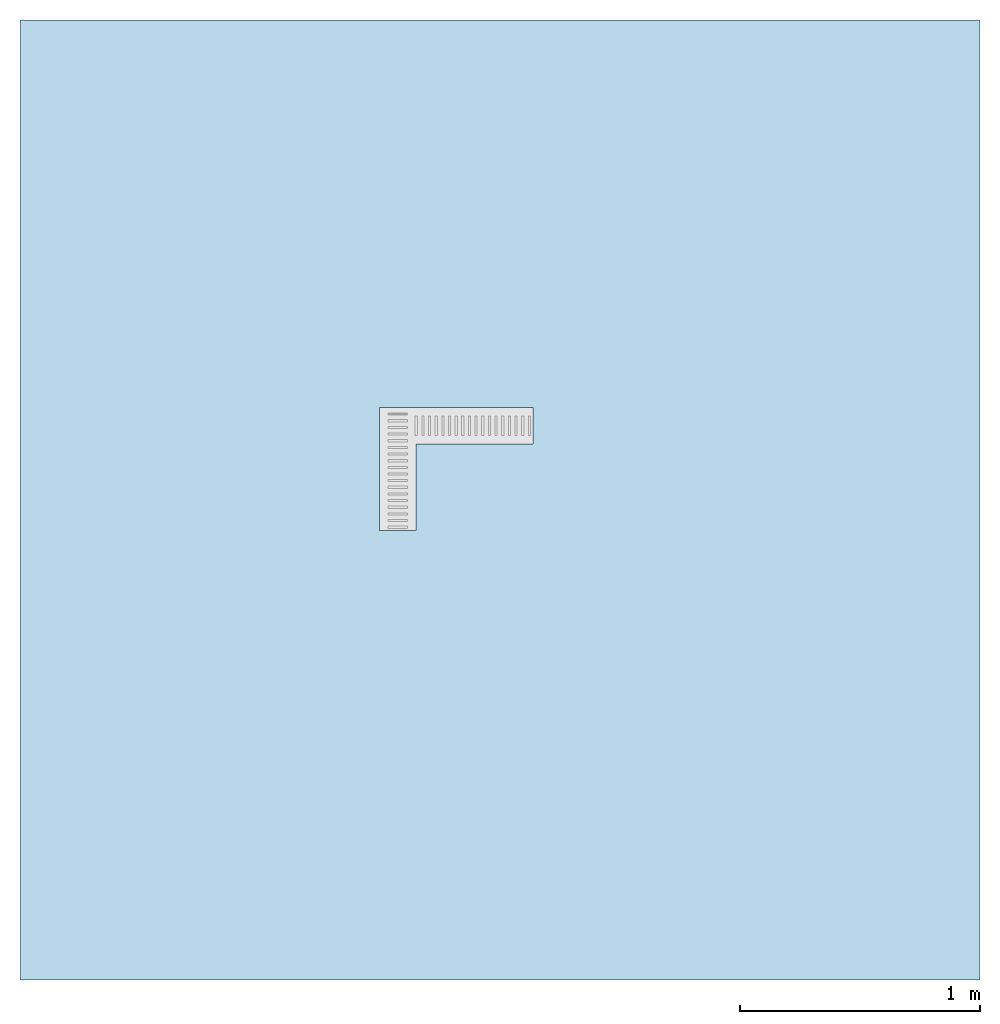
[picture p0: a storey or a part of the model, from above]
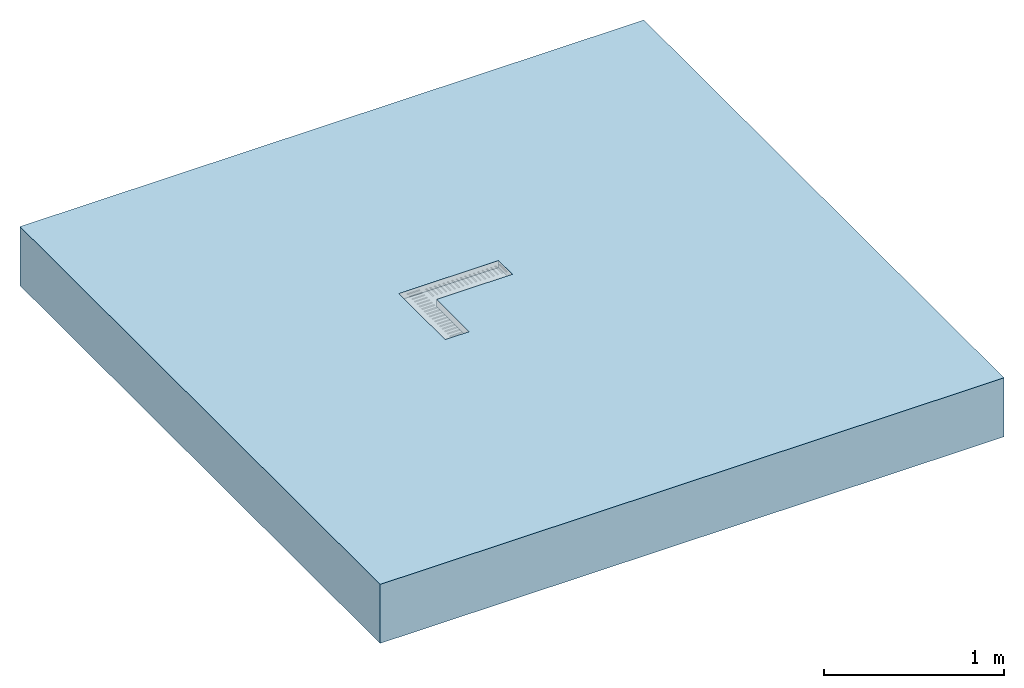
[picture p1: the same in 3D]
Properties of the parts of a building model (IFC2X3)

# File
Description: ViewDefinition [CoordinationView]
File name: 105259 - Level Invert Corner Unit.ifc
Time: 2014-03-20T14:34:00
Written by: Autodesk Revit 2013
Made in: 20120221_2030(x64)

# IfcProject, Project Number
LongName: Project Name; Phase: Project Status

# IfcSite, Default
RefLatitude: 42, 21, 30, 344238; RefLongitude: -71, -3, -35, -194702; RefElevation: 0 mm

# IfcBuilding
Pset_BuildingCommon - NumberOfStoreys: 1
Other - Project Issue Date: Issue Date; Project Address: ## Street City, State Zip; Project Number: Project Number; Project Status: Project Status; Project Name: Project Name; Client Name: Owner

# IfcBuildingStorey, Level 1
LongName: Level 1; Elevation: 0 mm
Constraints - Elevation Base: 0; Elevation: 0 mm
Graphics - Color: 0; Symbol at End 2 Default: yes; Line Weight: 1; Line Pattern: Center; Symbol: M_Level Head - Circle: M_Level Head - Circle; Symbol at End 1 Default: no
Identity Data - Building Story: yes; Structural: no; Name: Level 1
Dimensions - Computation Height: 0 mm

# IfcBuildingElementProxy: 105259 - Level Invert Corner Unit, ACO BD Deckline 125 Corner Unit:105259 - Level Invert Corner Unit:105259 - Level Invert Corner Unit:216780
In: Level 1
Material: Steel, Galvanized
Construction - 105523 - A15 Slotted Grating - 500mm Long - Galvanized Finish.: no; 10735 - C250 Composite Grating - 500mm Long - White Coloured Finish.: no; 105525 - C250 Slotted Grating - 500mm Long - Galvanized Finish.: no; 15704 - C250 Composite Grating - 500mm Long - Black Coloured Finish.: no; 105509 - C250 Perforated Grating - 500mm Long - Galvanized Finish.: no; End Plate Invert 1: no; End Plate Invert 2: no; Grating: yes
Dimensions - Volume: 2597170 mm3
Phasing - Phase Created: New Construction
Constraints - Level: Level: Level 1; Moves With Nearby Elements: no
Pset_BuildingElementProxyCommon - Reference: 105259 - Level Invert Corner Unit
Model Properties - Grating Product Code 105509: Load Class C250 - Perforated Galvanized Steel - 500mm long - 2.3kg; Grating Product Code 15704: Load Class C250 - Composite Black - 500mm long - 1.2kg; Grating Product Code 10735: Load Class C250 - Composite White - 500mm long - 1.2kg; Grating Product Code 105523: Load Class A15 - Slotted Galvanized Steel - 500mm long - 1.0kg; Grating Product Code 105525: Load Class C250 - Slotted Galvanized Steel - 500mm long - 2.3kg
Identity Data - Fax: +44 (0)1462 851490; Manufacturer: ACO Building Drainage; Watermarked By: www.acobd.com; E-mail Sales: abdcommercial@aco.co.uk; Telephone: +44 (0)1462 816666; Website: www.acobd.com; Address: ACO Business Centre, Caxton Road, Bedford, MK41 0LF; E-mail Technical: abdtechnical@aco.co.uk; Watermark2: This file is water marked and users are prohibited to reproduce, adapt, distribute this information.; Watermarked With: BIM Manager Premium Suite.; Watermark1: This file is the property of ACO Technologies PLC.; Cost: 0
General - Seal Recycled Material Content: 0%; Channel Colour: Galvanized; Price: POA - contact ACO; Product Standard: BS EN 1433:2002, CE marked; Product Code: 105259; Product Type: shallow invert surface water drainage system; Seal Colour: Black; Channel Recyclable: Fully recyclable; Seal Recyclable: Fully recyclable; Channel Material: Hot Dipped Galvanized Steel; Seal Material: Neoprene; NBS Specification: NBS Section Q10 Kerbs/edgings/channels/paving accessories, Clause 180 Drainage Channel Systems; Product Range: ACO Deckline 125; Product Description: ACO Deckline Level Invert Channel Corner; Maintenance guidelines: X:\Electronic Literature\Building Drainage Literature\Deckline\Deckline 125.PDF; Installation guidelines: X:\Electronic Literature\Building Drainage Literature\Deckline\Deckline 125.PDF; Weight (Kg): 4.0; Dimensions (LxWxH): 514 / 639 x 153 x 63; Channel Recycled Material Content: 25 - 30 %; Load Class: A15 - C250

# IfcOpeningElement: Recess
In: Level 1
Structural - Structural: no; Enable Analytical Model: no
Phasing - Phase Created: New Construction
Dimensions - Thickness: 400 mm; Area: 16000000 mm2; Volume: 6392838814 mm3; Perimeter: 16000 mm
Constraints - Room Bounding: yes; Related to Mass: no; Height Offset From Level: 0 mm; Level: Level: Level 1
Construction - Function: 0; Default Thickness: 400 mm
Graphics - Coarse Scale Fill Color: 0
Analytical Properties - Thermal mass: 604440; Absorptance: 0.1; Roughness: 1; Heat Transfer Coefficient (U): 2.615; Thermal Resistance (R): 0.382409
Materials and Finishes - Structural Material: Concrete, Broom Finish

# IfcSlab: Floor:Generic Floor - 400mm, Floor:Generic Floor - 400mm:193825
In: Level 1
PredefinedType: FLOOR; Material: Concrete, Broom Finish 400 mm
Structural - Structural: no; Enable Analytical Model: no
Phasing - Phase Created: New Construction
Dimensions - Thickness: 400 mm; Area: 16000000 mm2; Volume: 6392838814 mm3; Perimeter: 16000 mm
Constraints - Room Bounding: yes; Related to Mass: no; Height Offset From Level: 0 mm; Level: Level: Level 1
Pset_SlabCommon - Reference: Generic Floor - 400mm; IsExternal: no; LoadBearing: yes
Construction - Function: 0; Default Thickness: 400 mm
Graphics - Coarse Scale Fill Color: 0
Analytical Properties - Thermal mass: 604440; Absorptance: 0.1; Roughness: 1; Heat Transfer Coefficient (U): 2.615; Thermal Resistance (R): 0.382409
Materials and Finishes - Structural Material: Concrete, Broom Finish
